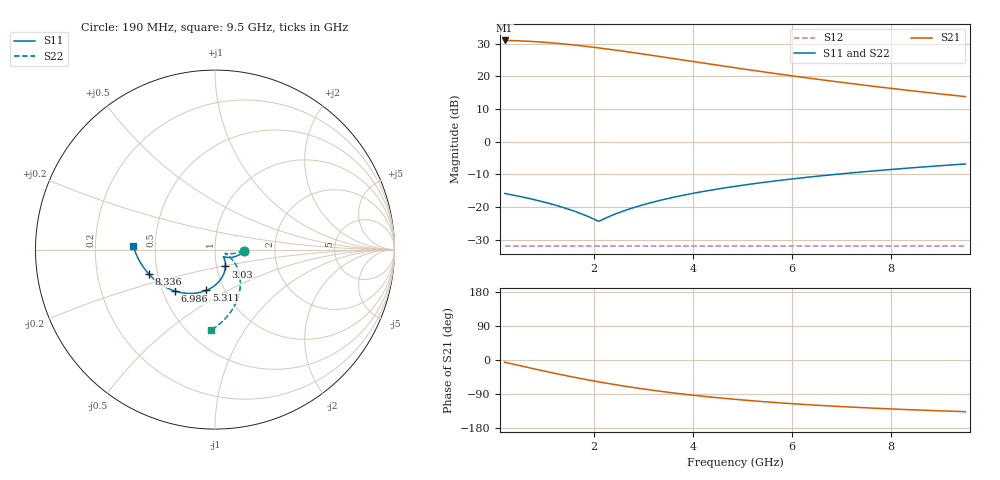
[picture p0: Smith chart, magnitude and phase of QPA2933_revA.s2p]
! written by passband
# GHZ S MA R 50
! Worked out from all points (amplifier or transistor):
!   201 points, 190 MHz to 9.5 GHz, reference 50 ohm
!   highest |S21| = 31.0 dB at 190 MHz (marker M1)
!   |S21| within 3 dB of that: start of sweep to 2.451 GHz
!   unconditionally stable (mu >= 1): 1.172 GHz to end of sweep
!   at 1.726 GHz: K = 1.04, MAG = 29.5 dB, |S12| = -32.0 dB
!   at 4.845 GHz: K = 1.56, MAG = 22.9 dB, |S12| = -32.0 dB
!   at 9.5 GHz: K = 2.55, MAG = 16.0 dB, |S12| = -32.0 dB
!   S11 on the Smith chart (normalised r, x): 190 MHz: 1.38, -0.03; 3.03 GHz: 1.10, -0.21; 5.311 GHz: 0.82, -0.39; 6.986 GHz: 0.58, -0.30; 8.336 GHz: 0.45, -0.14; 9.5 GHz: 0.37, +0.02
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0.19  0.1614 -3.6  35.39 -5.7  0.02512 -8.7  0.1594 -1.9
0.3762  0.1515 -7.2  35.14 -11.3  0.02512 -17.2  0.1496 -3.7
0.5624  0.1415 -10.8  34.72 -16.8  0.02512 -25.7  0.1398 -5.5
0.79515  0.1291 -15.3  33.99 -23.6  0.02512 -36.3  0.1275 -7.8
1.0279  0.1167 -19.7  33.06 -30.3  0.02512 -46.9  0.1153 -10.0
1.4003  0.09684 -26.9  31.24 -40.5  0.02512 -63.9  0.09564 -13.7
1.7727  0.07697 -34.0  29.14 -50.0  0.02512 -80.9  0.07602 -17.3
2.052  0.06207 -39.4  27.47 -56.7  0.02512 -93.6  0.0613 -20.1
2.3313  0.07292 -44.7  25.78 -63.1  0.02512 -106.3  0.07202 -22.8
2.7037  0.09278 -51.9  23.56 -70.9  0.02512 -123.3  0.09164 -26.4
3.02955  0.1102 -58.1  21.69 -77.1  0.02512 -138.2  0.1088 -29.6
3.30885  0.1251 -63.5  20.18 -82.1  0.02512 -150.9  0.1235 -32.3
3.6347  0.1425 -69.7  18.53 -87.5  0.02512 -165.8  0.1407 -35.5
4.0071  0.1623 -76.9  16.8 -93.0  0.02512 177.2  0.1603 -39.2
4.42605  0.1847 -84.9  15.06 -98.7  0.02512 158.1  0.1824 -43.3
4.845  0.207 -92.9  13.51 -103.8  0.02512 139.0  0.2045 -47.4
5.3105  0.2319 -101.9  12.02 -108.8  0.02512 117.8  0.229 -51.9
6.4277  0.2915 -123.3  9.189 -118.8  0.02512 66.8  0.2879 -62.8
6.9863  0.3213 -134.0  8.101 -122.9  0.02512 41.3  0.3173 -68.3
7.96385  0.3734 -152.8  6.58 -129.0  0.02512 -3.3  0.3688 -77.8
8.33625  0.3933 -159.9  6.104 -131.0  0.02512 -20.2  0.3884 -81.5
9.5  0.4554 177.8  4.894 -136.4  0.02512 -73.3  0.4498 -92.9
